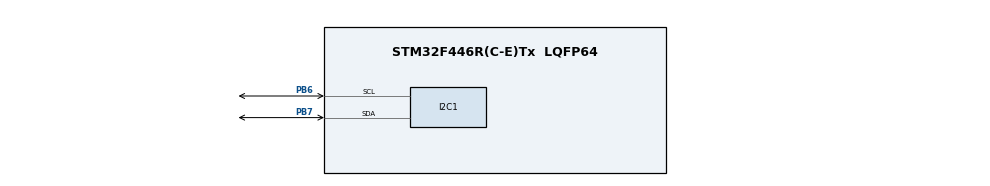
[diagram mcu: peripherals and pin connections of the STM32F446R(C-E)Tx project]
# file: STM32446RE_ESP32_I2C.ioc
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Mcu.Family=STM32F4
Mcu.Name=STM32F446R(C-E)Tx
Mcu.Package=LQFP64
NVIC.PriorityGroup=NVIC_PRIORITYGROUP_4
PA13.Mode=Serial_Wire
PA13.Signal=SYS_JTMS-SWDIO
PA14.Mode=Serial_Wire
PA14.Signal=SYS_JTCK-SWCLK
PB6.Mode=I2C
PB6.Signal=I2C1_SCL
PB7.Mode=I2C
PB7.Signal=I2C1_SDA
PH0-OSC_IN.Mode=HSE-External-Oscillator
PH0-OSC_IN.Signal=RCC_OSC_IN
PH1-OSC_OUT.Mode=HSE-External-Oscillator
PH1-OSC_OUT.Signal=RCC_OSC_OUT
ProjectManager.HeapSize=0x200
ProjectManager.StackSize=0x400
ProjectManager.TargetToolchain=STM32CubeIDE
RCC.AHBFreq_Value=16000000
RCC.APB1Freq_Value=16000000
RCC.APB1TimFreq_Value=16000000
RCC.APB2Freq_Value=16000000
RCC.APB2TimFreq_Value=16000000
RCC.CortexFreq_Value=16000000
RCC.HCLKFreq_Value=16000000
RCC.HSE_VALUE=25000000
RCC.SYSCLKFreq_VALUE=16000000
RCC.USBFreq_Value=96000000
RCC.VCOOutputFreq_Value=192000000
board=custom

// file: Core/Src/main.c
#include "main.h"

I2C_HandleTypeDef hi2c1;

uint8_t data = 0x01;   // Data to send to ESP32

/* Function Prototypes */
void SystemClock_Config(void);
static void MX_GPIO_Init(void);
static void MX_I2C1_Init(void);

int main(void)
{
  HAL_Init();
  SystemClock_Config();
  MX_GPIO_Init();
  MX_I2C1_Init();

  HAL_Delay(1000);   // Wait for ESP32 to initialize

  while (1)
  {
    HAL_I2C_Master_Transmit(&hi2c1, (0x08 << 1), &data, 1, HAL_MAX_DELAY);
    HAL_Delay(1000);  // Send every 1 second
  }
}

void SystemClock_Config(void)
{
  RCC_OscInitTypeDef RCC_OscInitStruct = {0};
  RCC_ClkInitTypeDef RCC_ClkInitStruct = {0};
  __HAL_RCC_PWR_CLK_ENABLE();
  __HAL_PWR_VOLTAGESCALING_CONFIG(PWR_REGULATOR_VOLTAGE_SCALE2);

  /* 1️⃣ Configure HSE and PLL */
  RCC_OscInitStruct.OscillatorType = RCC_OSCILLATORTYPE_HSE;
  RCC_OscInitStruct.HSEState = RCC_HSE_ON;
  RCC_OscInitStruct.PLL.PLLState = RCC_PLL_ON;
  RCC_OscInitStruct.PLL.PLLSource = RCC_PLLSOURCE_HSE;

  RCC_OscInitStruct.PLL.PLLM = 8;      // 8 MHz / 8 = 1 MHz
  RCC_OscInitStruct.PLL.PLLN = 336;    // 1 MHz * 336 = 336 MHz
  RCC_OscInitStruct.PLL.PLLP = RCC_PLLP_DIV4;  // 336 / 4 = 84 MHz
  RCC_OscInitStruct.PLL.PLLQ = 7;

  if (HAL_RCC_OscConfig(&RCC_OscInitStruct) != HAL_OK)
  {
    Error_Handler();
  }

  /* 2️⃣ Select PLL as system clock source */
  RCC_ClkInitStruct.ClockType = RCC_CLOCKTYPE_SYSCLK |
                                RCC_CLOCKTYPE_HCLK   |
                                RCC_CLOCKTYPE_PCLK1  |
                                RCC_CLOCKTYPE_PCLK2;

  RCC_ClkInitStruct.SYSCLKSource = RCC_SYSCLKSOURCE_PLLCLK;
  RCC_ClkInitStruct.AHBCLKDivider = RCC_SYSCLK_DIV1;
  RCC_ClkInitStruct.APB1CLKDivider = RCC_HCLK_DIV2;   // 42 MHz
  RCC_ClkInitStruct.APB2CLKDivider = RCC_HCLK_DIV1;   // 84 MHz

  if (HAL_RCC_ClockConfig(&RCC_ClkInitStruct, FLASH_LATENCY_2) != HAL_OK)
  {
    Error_Handler();
  }
}

static void MX_I2C1_Init(void)
{
  hi2c1.Instance = I2C1;
  hi2c1.Init.ClockSpeed = 100000;  // 100 kHz
  hi2c1.Init.DutyCycle = I2C_DUTYCYCLE_2;
  hi2c1.Init.OwnAddress1 = 0;
  hi2c1.Init.AddressingMode = I2C_ADDRESSINGMODE_7BIT;
  hi2c1.Init.DualAddressMode = I2C_DUALADDRESS_DISABLE;
  hi2c1.Init.OwnAddress2 = 0;
  hi2c1.Init.GeneralCallMode = I2C_GENERALCALL_DISABLE;
  hi2c1.Init.NoStretchMode = I2C_NOSTRETCH_DISABLE;

  if (HAL_I2C_Init(&hi2c1) != HAL_OK)
  {
    Error_Handler();
  }
}

static void MX_GPIO_Init(void)
{
  __HAL_RCC_GPIOB_CLK_ENABLE();

  GPIO_InitTypeDef GPIO_InitStruct = {0};

  GPIO_InitStruct.Pin = GPIO_PIN_8 | GPIO_PIN_9;
  GPIO_InitStruct.Mode = GPIO_MODE_AF_OD;   // Open Drain
  GPIO_InitStruct.Pull = GPIO_NOPULL;       // External pull-up used
  GPIO_InitStruct.Speed = GPIO_SPEED_FREQ_VERY_HIGH;
  GPIO_InitStruct.Alternate = GPIO_AF4_I2C1;

  HAL_GPIO_Init(GPIOB, &GPIO_InitStruct);
}

void Error_Handler(void)
{
  __disable_irq();
  while (1)
  {
  }
}
